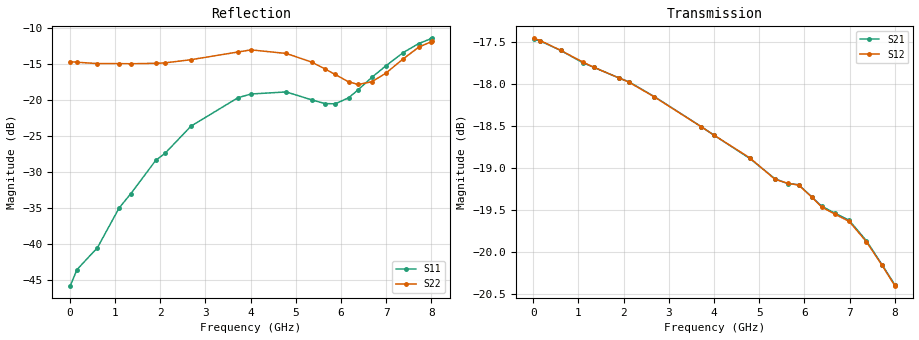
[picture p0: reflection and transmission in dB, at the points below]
! DEVICE ID: PE43712
! File Path: z:\PE43713\PE43713_CHAR_NOM_04292014\AMB\3p300\LS_ATT_16p25dB\PE43713_AMB_3p300V_3p000V_0p000V_LS_ATT_16p25dB_S2P_SN_10_A0139A.s2p
! Serial: 10
! Lot: A0139A
! Temp: 25C
! VDD: 3.300
! VSS: 0.000
! Control_Hi: 3.000
! Control_Lo: 0.000
! Attenuation Step: 16.25dB
! Port 1: RF1
! Port 2: RF2
! ThroughPath:1-2
! IDD: 0.0001462178
! ISS: -2.018e-007
#  Hz  S  RI  R  50
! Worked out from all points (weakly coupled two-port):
!   801 points, 10 MHz to 8.01 GHz, reference 50 ohm
!   highest |S21| = -17.46 dB at 10 MHz (marker M1); lowest = -20.4 dB at 8 GHz (marker M2)
!   lowest |S11| = -45.8 dB at 10 MHz (marker M3), VSWR 1.01, Z = 50.5 + j0.0454 ohm
!   |S11| at or under -10 dB: start of sweep to end of sweep
!   |S22| runs from -17.9 to -11.9 dB; largest |S21 - S12| = 0.00048
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1e7  0.00513 0.000449  0.134 -0.000698  0.1341 -0.000651  -0.184 0.00121
1.6e8  0.00623 0.00237  0.1333 -0.00878  0.1334 -0.00876  -0.1818 0.0116
6.1e8  0.00576 0.00747  0.1281 -0.0314  0.1281 -0.0314  -0.1744 0.0373
1.09e9  0.00488 0.0171  0.1186 -0.0525  0.1187 -0.0526  -0.166 0.065
1.35e9  0.00588 0.0216  0.1125 -0.0628  0.1125 -0.0628  -0.1598 0.078
1.9e9  0.0116 0.0362  0.0967 -0.0823  0.0967 -0.0823  -0.1414 0.1099
2.11e9  0.014 0.0403  0.0898 -0.0889  0.0898 -0.0888  -0.1351 0.1195
2.68e9  0.0255 0.0605  0.0688 -0.1029  0.0687 -0.1029  -0.1092 0.1551
3.72e9  0.0319 0.0983  0.0259 -0.1159  0.0258 -0.1159  -0.0827 0.1979
4.01e9  0.0319 0.105  0.014 -0.1165  0.014 -0.1165  -0.0814 0.2064
4.79e9  0.0326 0.1086  -0.0164 -0.1125  -0.0164 -0.1126  -0.067 0.1985
5.35e9  0.0437 0.0899  -0.0358 -0.1046  -0.0358 -0.1045  -0.0505 0.1755
5.64e9  0.0538 0.0774  -0.0449 -0.1002  -0.0448 -0.1003  -0.0315 0.1611
5.87e9  0.0636 0.0688  -0.053 -0.096  -0.0529 -0.096  -0.0124 0.1493
6.17e9  0.0822 0.0626  -0.0624 -0.0879  -0.0622 -0.088  0.0176 0.132
6.38e9  0.0998 0.0617  -0.0673 -0.0825  -0.0671 -0.0825  0.0417 0.1207
6.68e9  0.1297 0.0602  -0.0746 -0.0745  -0.0745 -0.0744  0.0786 0.1077
6.99e9  0.1594 0.0635  -0.0818 -0.0649  -0.0816 -0.0649  0.1123 0.1035
7.37e9  0.1996 0.071  -0.0878 -0.051  -0.0877 -0.0509  0.1578 0.1085
7.72e9  0.2322 0.0796  -0.0901 -0.0391  -0.09 -0.0391  0.1988 0.119
8e9  0.2504 0.0895  -0.0907 -0.0301  -0.0905 -0.0303  0.2199 0.1253
8.01e9  0.2509 0.0902  -0.0907 -0.0299  -0.0906 -0.0301  0.2206 0.1255
